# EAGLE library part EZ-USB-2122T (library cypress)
Microcontroller with USB port

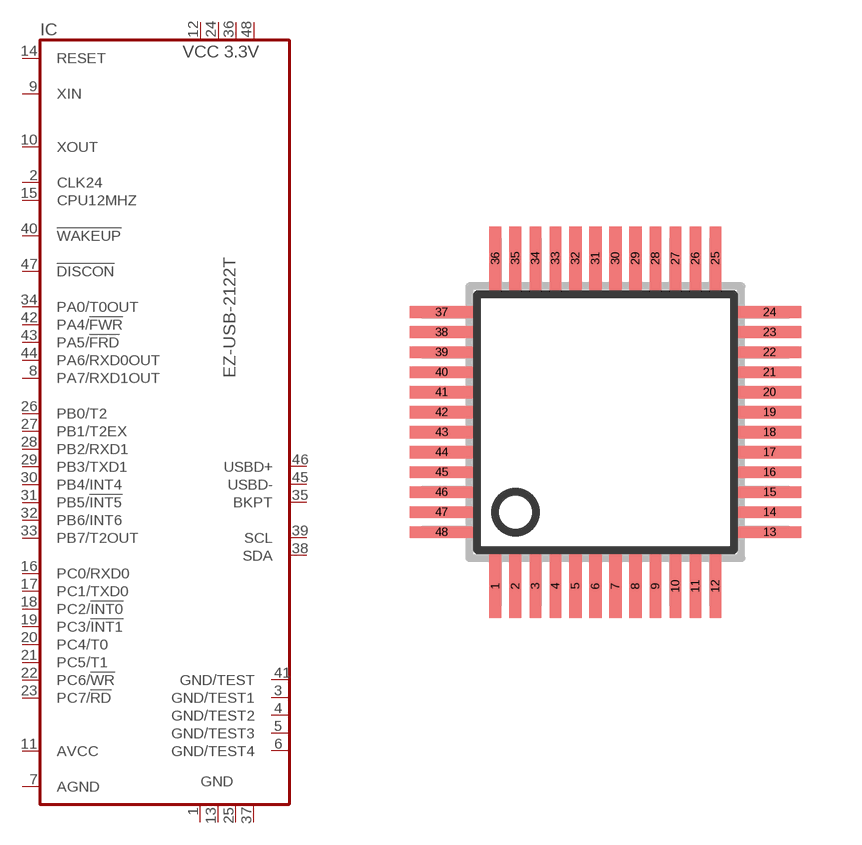
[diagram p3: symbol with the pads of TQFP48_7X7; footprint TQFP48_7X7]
Designator prefix IC

## EZ-USB-2122T (OC_FARNELL: unknown; OC_NEWARK: unknown)  [TQFP48_7X7]
1  GND  pwr
2  CLK24  out
3  GND/TEST1  pwr
4  GND/TEST2  pwr
5  GND/TEST3  pwr
6  GND/TEST4  pwr
7  AGND  pwr
8  PA7/RXD1OUT
9  XIN  in
10  XOUT  out
11  AVCC  pwr
12  VCC3.3  pwr
13  GND  pwr
14  RESET  in
15  CPU12MHZ  in
16  PC0/RXD0
17  PC1/TXD0
18  PC2/!INT0
19  PC3/!INT1
20  PC4/T0
21  PC5/T1
22  PC6/!WR
23  PC7/!RD
24  VCC3.3  pwr
25  GND  pwr
26  PB0/T2
27  PB1/T2EX
28  PB2/RXD1
29  PB3/TXD1
30  PB4/INT4
31  PB5/!INT5
32  PB6/INT6
33  PB7/T2OUT
34  PA0/T0OUT
35  BKPT  out
36  VCC3.3  pwr
37  GND  pwr
38  SDA  oc
39  SCL  oc
40  !WAKEUP  in
41  GND/TEST  pwr
42  PA4/!FWR
43  PA5/!FRD
44  PA6/RXD0OUT
45  USBD-  hiz
46  USBD+  hiz
47  !DISCON  out
48  VCC3.3  pwr

## Footprint TQFP48_7X7 (pad centres in mm)
Thin Quad Flat Package from SMD-IPC.lbr SQFP48 7x7
smd 0.3 x 1.6: 1 -2.75,-4.1; 2 -2.25,-4.1; 3 -1.75,-4.1; 4 -1.25,-4.1; 5 -0.75,-4.1; 6 -0.25,-4.1; 7 0.25,-4.1; 8 0.75,-4.1; 9 1.25,-4.1; 10 1.75,-4.1; 11 2.25,-4.1; 12 2.75,-4.1; 25 2.75,4.1; 26 2.25,4.1; 27 1.75,4.1; 28 1.25,4.1; 29 0.75,4.1; 30 0.25,4.1; 31 -0.25,4.1; 32 -0.75,4.1; 33 -1.25,4.1; 34 -1.75,4.1; 35 -2.25,4.1; 36 -2.75,4.1
smd 1.6 x 0.3: 13 4.1,-2.75; 14 4.1,-2.25; 15 4.1,-1.75; 16 4.1,-1.25; 17 4.1,-0.75; 18 4.1,-0.25; 19 4.1,0.25; 20 4.1,0.75; 21 4.1,1.25; 22 4.1,1.75; 23 4.1,2.25; 24 4.1,2.75; 37 -4.1,2.75; 38 -4.1,2.25; 39 -4.1,1.75; 40 -4.1,1.25; 41 -4.1,0.75; 42 -4.1,0.25; 43 -4.1,-0.25; 44 -4.1,-0.75; 45 -4.1,-1.25; 46 -4.1,-1.75; 47 -4.1,-2.25; 48 -4.1,-2.75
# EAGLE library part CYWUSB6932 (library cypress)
WirelessUSB LS 2.4 GHz DSSS Radio SoC Source: http://v4.cypress.com/cfuploads/img/products/cywusb6934.pdf

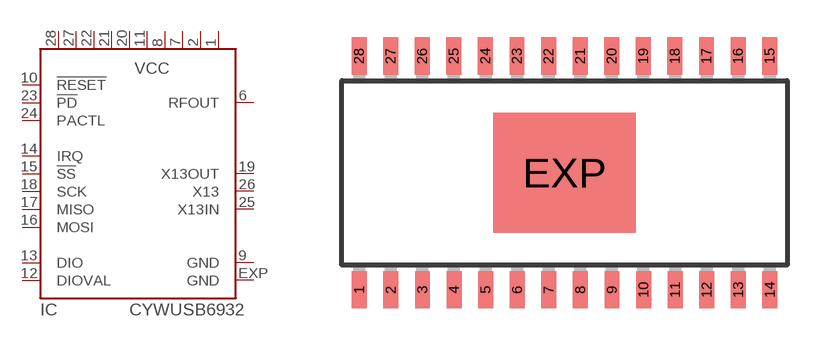
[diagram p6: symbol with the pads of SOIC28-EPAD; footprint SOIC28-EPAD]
Designator prefix IC

## CYWUSB6932-SE28 (OC_FARNELL: unknown; OC_NEWARK: unknown)  [SOIC28-EPAD]
1  VCC  pwr
2  VCC  pwr
6  RFOUT  out
7  VCC  pwr
8  VCC  pwr
9  GND  pwr
10  !RESET  in
11  VCC  pwr
12  DIOVAL
13  DIO
14  IRQ  hiz
15  !SS  in
16  MOSI  in
17  MISO  hiz
18  SCK  in
19  X13OUT  out
20  VCC  pwr
21  VCC  pwr
22  VCC  pwr
23  !PD  in
24  PACTL
25  X13IN  in
26  X13  in
27  VCC  pwr
28  VCC  pwr
EXP  GND  pwr

## Footprint SOIC28-EPAD (pad centres in mm)
28-pin (300-Mil) SOIC EPAD SE28.3 Source: http://v4.cypress.com/cfuploads/img/products/cywusb6934.pdf
smd 0.6 x 1.5: 1 -8.25,-4.7; 2 -6.98,-4.7; 3 -5.71,-4.7; 4 -4.44,-4.7; 5 -3.17,-4.7; 6 -1.9,-4.7; 7 -0.63,-4.7; 8 0.64,-4.7; 9 1.91,-4.7; 10 3.18,-4.7; 11 4.45,-4.7; 12 5.72,-4.7; 13 6.99,-4.7; 14 8.26,-4.7; 15 8.25,4.7; 16 6.98,4.7; 17 5.71,4.7; 18 4.44,4.7; 19 3.17,4.7; 20 1.9,4.7; 21 0.63,4.7; 22 -0.64,4.7; 23 -1.91,4.7; 24 -3.18,4.7; 25 -4.45,4.7; 26 -5.72,4.7; 27 -6.99,4.7; 28 -8.26,4.7
smd 5.715 x 4.826: EXP 0,0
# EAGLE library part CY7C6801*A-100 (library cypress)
EZ-USB FX2LP (TM) USB Microcontroller Source: http://www.cypress.com .. cy7c68013a_5.pdf

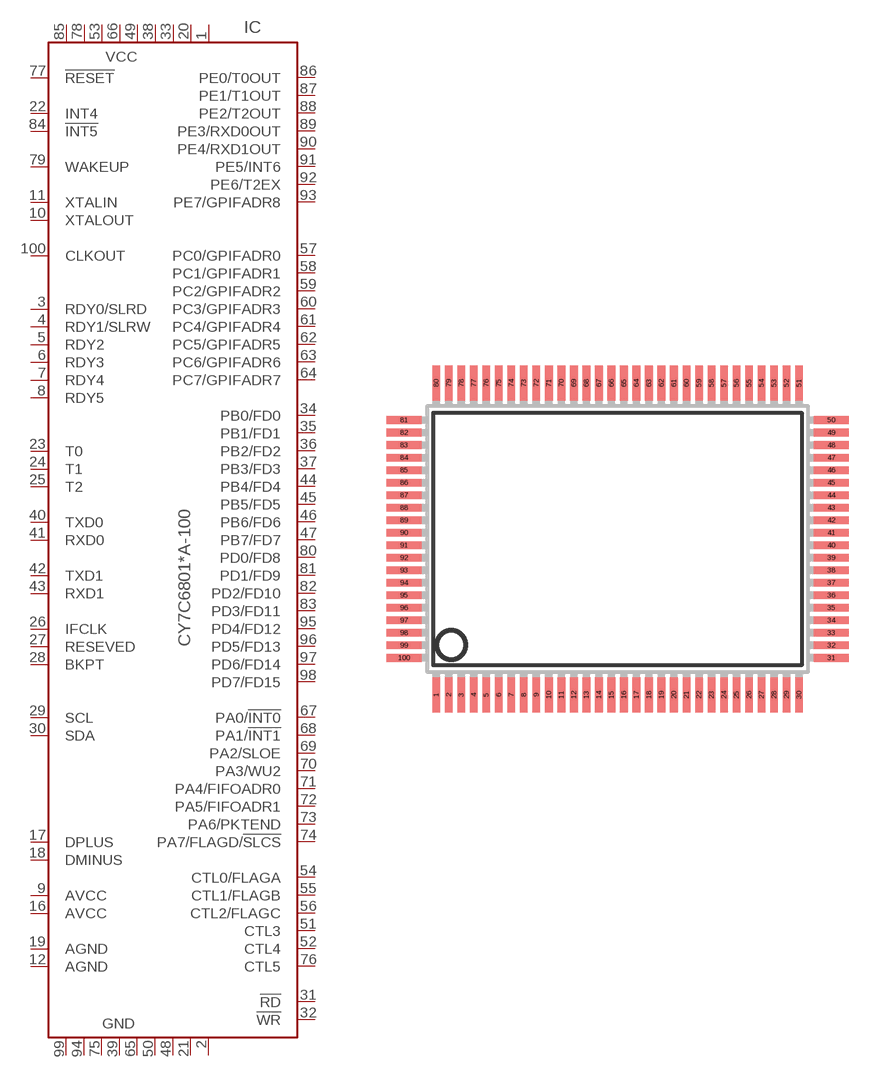
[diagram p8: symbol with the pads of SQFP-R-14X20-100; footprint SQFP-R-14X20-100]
Designator prefix IC

## CY7C68013A-100AXC (MF: CYPRESS SEMICONDUCTOR CORPORAT; MPN: CY7C68013A-100AXC; OC_FARNELL: 1269130; OC_NEWARK: 19M7106), CY7C68014A-100AXC (MF: CYPRESS SEMICONDUCTOR CORPORAT; MPN: CY7C68014A-100AXC; OC_FARNELL: 1269135; OC_NEWARK: 19M7117)  [SQFP-R-14X20-100]
1  VCC  in
2  GND  in
3  RDY0/SLRD  in
4  RDY1/SLRW  in
5  RDY2  in
6  RDY3  in
7  RDY4  in
8  RDY5  in
9  AVCC  in
10  XTALOUT  in
11  XTALIN  in
12  AGND  in
16  AVCC  in
17  DPLUS
18  DMINUS
19  AGND  in
20  VCC  in
21  GND  in
22  INT4  out
23  T0  out
24  T1  out
25  T2  out
26  IFCLK
27  RESEVED  in
28  BKPT  out
29  SCL  out
30  SDA
31  !RD  out
32  !WR  out
33  VCC  in
34  PB0/FD0
35  PB1/FD1
36  PB2/FD2
37  PB3/FD3
38  VCC  in
39  GND  in
40  TXD0  in
41  RXD0  out
42  TXD1  in
43  RXD1  out
44  PB4/FD4
45  PB5/FD5
46  PB6/FD6
47  PB7/FD7
48  GND  in
49  VCC  in
50  GND  in
51  CTL3  in
52  CTL4  in
53  VCC  in
54  CTL0/FLAGA  out
55  CTL1/FLAGB  out
56  CTL2/FLAGC  out
57  PC0/GPIFADR0
58  PC1/GPIFADR1
59  PC2/GPIFADR2
60  PC3/GPIFADR3
61  PC4/GPIFADR4
62  PC5/GPIFADR5
63  PC6/GPIFADR6
64  PC7/GPIFADR7
65  GND  in
66  VCC  in
67  PA0/!INT0
68  PA1/!INT1
69  PA2/SLOE
70  PA3/WU2
71  PA4/FIFOADR0
72  PA5/FIFOADR1
73  PA6/PKTEND
74  PA7/FLAGD/!SLCS
75  GND  in
76  CTL5
77  !RESET
78  VCC  in
79  WAKEUP  in
80  PD0/FD8
81  PD1/FD9
82  PD2/FD10
83  PD3/FD11
84  !INT5  out
85  VCC  in
86  PE0/T0OUT
87  PE1/T1OUT
88  PE2/T2OUT
89  PE3/RXD0OUT
90  PE4/RXD1OUT
91  PE5/INT6
92  PE6/T2EX
93  PE7/GPIFADR8
94  GND  in
95  PD4/FD12
96  PD5/FD13
97  PD6/FD14
98  PD7/FD15
99  GND  in
100  CLKOUT  in

## CY7C68013A-100AXI (MPN: CY7C68013A-100AXI; OC_FARNELL: unknown; OC_NEWARK: 19M7107)  [SQFP-R-14X20-100]
Pads as for SQFP-R-14X20-100

## Footprint SQFP-R-14X20-100 (pad centres in mm)
QFP100 shrink quad flat pack, rectangle
smd 0.4 x 1.8: 1 -9.425,-8.1; 2 -8.775,-8.1; 3 -8.125,-8.1; 4 -7.475,-8.1; 5 -6.825,-8.1; 6 -6.175,-8.1; 7 -5.525,-8.1; 8 -4.875,-8.1; 9 -4.225,-8.1; 10 -3.575,-8.1; 11 -2.925,-8.1; 12 -2.275,-8.1; 13 -1.625,-8.1; 14 -0.975,-8.1; 15 -0.325,-8.1; 16 0.325,-8.1; 17 0.975,-8.1; 18 1.625,-8.1; 19 2.275,-8.1; 20 2.925,-8.1; 21 3.575,-8.1; 22 4.225,-8.1; 23 4.875,-8.1; 24 5.525,-8.1; 25 6.175,-8.1; 26 6.825,-8.1; 27 7.475,-8.1; 28 8.125,-8.1; 29 8.775,-8.1; 30 9.425,-8.1; 51 9.425,8.1; 52 8.775,8.1; 53 8.125,8.1; 54 7.475,8.1; 55 6.825,8.1; 56 6.175,8.1; 57 5.525,8.1; 58 4.875,8.1; 59 4.225,8.1; 60 3.575,8.1; 61 2.925,8.1; 62 2.275,8.1; 63 1.625,8.1; 64 0.975,8.1; 65 0.325,8.1; 66 -0.325,8.1; 67 -0.975,8.1; 68 -1.625,8.1; 69 -2.275,8.1; 70 -2.925,8.1; 71 -3.575,8.1; 72 -4.225,8.1; 73 -4.875,8.1; 74 -5.525,8.1; 75 -6.175,8.1; 76 -6.825,8.1; 77 -7.475,8.1; 78 -8.125,8.1; 79 -8.775,8.1; 80 -9.425,8.1
smd 1.8 x 0.4: 31 11.1,-6.175; 32 11.1,-5.525; 33 11.1,-4.875; 34 11.1,-4.225; 35 11.1,-3.575; 36 11.1,-2.925; 37 11.1,-2.275; 38 11.1,-1.625; 39 11.1,-0.975; 40 11.1,-0.325; 41 11.1,0.325; 42 11.1,0.975; 43 11.1,1.625; 44 11.1,2.275; 45 11.1,2.925; 46 11.1,3.575; 47 11.1,4.225; 48 11.1,4.875; 49 11.1,5.525; 50 11.1,6.175; 81 -11.1,6.175; 82 -11.1,5.525; 83 -11.1,4.875; 84 -11.1,4.225; 85 -11.1,3.575; 86 -11.1,2.925; 87 -11.1,2.275; 88 -11.1,1.625; 89 -11.1,0.975; 90 -11.1,0.325; 91 -11.1,-0.325; 92 -11.1,-0.975; 93 -11.1,-1.625; 94 -11.1,-2.275; 95 -11.1,-2.925; 96 -11.1,-3.575; 97 -11.1,-4.225; 98 -11.1,-4.875; 99 -11.1,-5.525; 100 -11.1,-6.175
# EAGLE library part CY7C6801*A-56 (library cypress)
EZ-USB FX2LP (TM) USB Microcontroller Source: http://www.cypress.com .. cy7c68013a_5.pdf

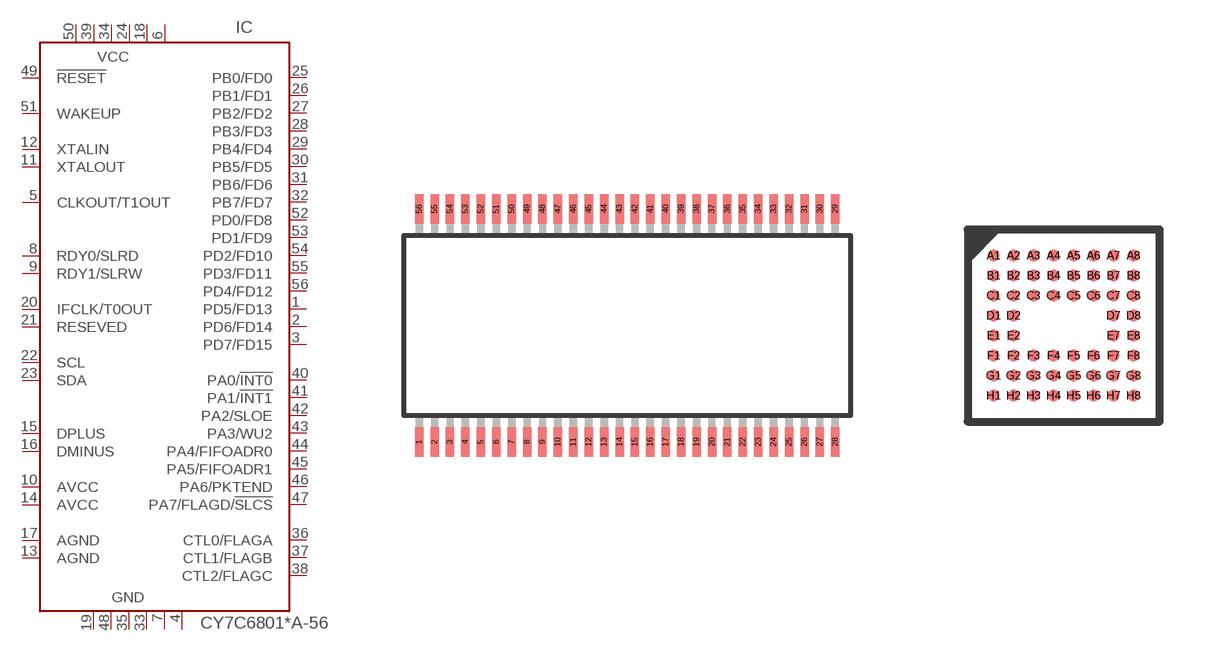
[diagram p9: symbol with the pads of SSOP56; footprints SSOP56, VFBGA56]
Designator prefix IC

## CY7C68013A-56PVXC (MF: CYPRESS SEMICONDUCTOR CORPORAT; MPN: CY7C68013A-56PVXC; OC_FARNELL: 1269134; OC_NEWARK: 19M7114), CY7C68014A-56PVXC (MF: CYPRESS SEMICONDUCTOR CORPORAT; MPN: CY7C68014A-56PVXC; OC_FARNELL: 1269140; OC_NEWARK: 19M7121)  [SSOP56]
1  PD5/FD13
2  PD6/FD14
3  PD7/FD15
4  GND  in
5  CLKOUT/T1OUT  in
6  VCC  in
7  GND  in
8  RDY0/SLRD  in
9  RDY1/SLRW  in
10  AVCC  in
11  XTALOUT  in
12  XTALIN  in
13  AGND  in
14  AVCC  in
15  DPLUS
16  DMINUS
17  AGND  in
18  VCC  in
19  GND  in
20  IFCLK/T0OUT
21  RESEVED  in
22  SCL  out
23  SDA
24  VCC  in
25  PB0/FD0
26  PB1/FD1
27  PB2/FD2
28  PB3/FD3
29  PB4/FD4
30  PB5/FD5
31  PB6/FD6
32  PB7/FD7
33  GND  in
34  VCC  in
35  GND  in
36  CTL0/FLAGA  out
37  CTL1/FLAGB  out
38  CTL2/FLAGC  out
39  VCC  in
40  PA0/!INT0
41  PA1/!INT1
42  PA2/SLOE
43  PA3/WU2
44  PA4/FIFOADR0
45  PA5/FIFOADR1
46  PA6/PKTEND
47  PA7/FLAGD/!SLCS
48  GND  in
49  !RESET  in
50  VCC  in
51  WAKEUP  in
52  PD0/FD8
53  PD1/FD9
54  PD2/FD10
55  PD3/FD11
56  PD4/FD12

## CY7C68013A-56BAXC (MF: CYPRESS SEMICONDUCTOR CORPORAT; MPN: CY7C68013A-56BAXC; OC_FARNELL: 1269132; OC_NEWARK: 19M7110), CY7C68014A-56BAXC (MPN: CY7C68014A-56BAXC; OC_FARNELL: 1269138; OC_NEWARK: 23M5564)  [VFBGA56]
A1  RDY0/SLRD  in
A2  PD7/FD15
A3  PD5/FD13
A4  GND  in
A5  VCC  in
A6  PD3/FD11
A7  PD1/FD9
A8  PD0/FD8
B1  RDY1/SLRW  in
B2  CLKOUT/T1OUT  in
B3  PD4/FD12
B4  GND  in
B5  VCC  in
B6  PD2/FD10
B7  WAKEUP  in
B8  !RESET  in
C1  XTALIN  in
C2  XTALOUT  in
C3  PD6/FD14
C4  GND  in
C5  VCC  in
C6  PA7/FLAGD/!SLCS
C7  PA6/PKTEND
C8  PA5/FIFOADR1
D1  AVCC  in
D2  AVCC  in
D7  GND  in
D8  GND  in
E1  DMINUS
E2  DPLUS
E7  VCC  in
E8  VCC  in
F1  AGND  in
F2  AGND  in
F3  SCL  out
F4  PB1/FD1
F5  PB6/FD6
F6  PA4/FIFOADR0
F7  PA3/WU2
F8  PA2/SLOE
G1  VCC  in
G2  IFCLK/T0OUT
G3  SDA
G4  PB3/FD3
G5  PB5/FD5
G6  PA1/!INT1
G7  CTL1/FLAGB  out
G8  PA0/!INT0
H1  GND  in
H2  RESEVED  in
H3  PB0/FD0
H4  PB2/FD2
H5  PB4/FD4
H6  PB7/FD7
H7  CTL0/FLAGA  out
H8  CTL2/FLAGC  out

## CY7C68013A-56PVXI (MPN: CY7C68013A-56PVXI; OC_FARNELL: 1761053; OC_NEWARK: 19M7116)  [SSOP56]
Pads as for SSOP56

## Footprint SSOP56 (pad centres in mm)
56-lead Shrunk Small Outline Package O56 Source: Source: http://www.cypress.com .. cy7c68013a_5.pdf
smd 0.35 x 1.2: 1 -8.572,-4.8; 2 -7.938,-4.8; 3 -7.303,-4.8; 4 -6.668,-4.8; 5 -6.032,-4.8; 6 -5.397,-4.8; 7 -4.763,-4.8; 8 -4.128,-4.8; 9 -3.493,-4.8; 10 -2.857,-4.8; 11 -2.223,-4.8; 12 -1.587,-4.8; 13 -0.953,-4.8; 14 -0.318,-4.8; 15 0.318,-4.8; 16 0.953,-4.8; 17 1.587,-4.8; 18 2.223,-4.8; 19 2.857,-4.8; 20 3.493,-4.8; 21 4.128,-4.8; 22 4.763,-4.8; 23 5.397,-4.8; 24 6.032,-4.8; 25 6.668,-4.8; 26 7.303,-4.8; 27 7.938,-4.8; 28 8.572,-4.8; 29 8.572,4.8; 30 7.938,4.8; 31 7.303,4.8; 32 6.668,4.8; 33 6.032,4.8; 34 5.397,4.8; 35 4.763,4.8; 36 4.128,4.8; 37 3.493,4.8; 38 2.857,4.8; 39 2.223,4.8; 40 1.587,4.8; 41 0.953,4.8; 42 0.318,4.8; 43 -0.318,4.8; 44 -0.953,4.8; 45 -1.587,4.8; 46 -2.223,4.8; 47 -2.857,4.8; 48 -3.493,4.8; 49 -4.128,4.8; 50 -4.763,4.8; 51 -5.397,4.8; 52 -6.032,4.8; 53 -6.668,4.8; 54 -7.303,4.8; 55 -7.938,4.8; 56 -8.572,4.8

## Footprint VFBGA56 (pad centres in mm)
VFBGA 56 Source: Source: http://www.cypress.com .. cy7c68013a_5.pdf
smd 0.3 x 0.3: A1 -1.75,1.75; A2 -1.25,1.75; A3 -0.75,1.75; A4 -0.25,1.75; A5 0.25,1.75; A6 0.75,1.75; A7 1.25,1.75; A8 1.75,1.75; B1 -1.75,1.25; B2 -1.25,1.25; B3 -0.75,1.25; B4 -0.25,1.25; B5 0.25,1.25; B6 0.75,1.25; B7 1.25,1.25; B8 1.75,1.25; C1 -1.75,0.75; C2 -1.25,0.75; C3 -0.75,0.75; C4 -0.25,0.75; C5 0.25,0.75; C6 0.75,0.75; C7 1.25,0.75; C8 1.75,0.75; D1 -1.75,0.25; D2 -1.25,0.25; D7 1.25,0.25; D8 1.75,0.25; E1 -1.75,-0.25; E2 -1.25,-0.25; E7 1.25,-0.25; E8 1.75,-0.25; F1 -1.75,-0.75; F2 -1.25,-0.75; F3 -0.75,-0.75; F4 -0.25,-0.75; F5 0.25,-0.75; F6 0.75,-0.75; F7 1.25,-0.75; F8 1.75,-0.75; G1 -1.75,-1.25; G2 -1.25,-1.25; G3 -0.75,-1.25; G4 -0.25,-1.25; G5 0.25,-1.25; G6 0.75,-1.25; G7 1.25,-1.25; G8 1.75,-1.25; H1 -1.75,-1.75; H2 -1.25,-1.75; H3 -0.75,-1.75; H4 -0.25,-1.75; H5 0.25,-1.75; H6 0.75,-1.75; H7 1.25,-1.75; H8 1.75,-1.75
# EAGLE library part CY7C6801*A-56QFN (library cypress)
EZ-USB FX2LP (TM) USB Microcontroller Source: http://www.cypress.com .. cy7c68013a_5.pdf

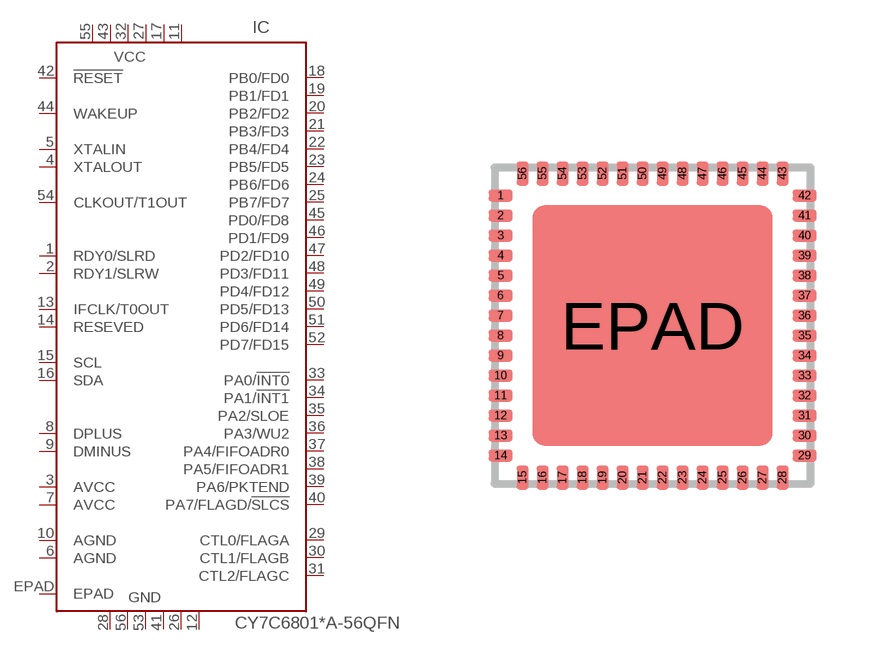
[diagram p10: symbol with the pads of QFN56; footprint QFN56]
Designator prefix IC

## CY7C68013A-56QFNLFXC (OC_FARNELL: unknown; OC_NEWARK: unknown), CY7C68014A-56QFNLFXC (OC_FARNELL: unknown; OC_NEWARK: unknown), CY7C68015A-56QFNLFXC (OC_FARNELL: unknown; OC_NEWARK: unknown), CY7C68016A-56QFNLFXC (OC_FARNELL: unknown; OC_NEWARK: unknown)  [QFN56]
1  RDY0/SLRD  in
2  RDY1/SLRW  in
3  AVCC  in
4  XTALOUT  in
5  XTALIN  in
6  AGND  in
7  AVCC  in
8  DPLUS
9  DMINUS
10  AGND  in
11  VCC  in
12  GND  in
13  IFCLK/T0OUT
14  RESEVED  in
15  SCL  out
16  SDA
17  VCC  in
18  PB0/FD0
19  PB1/FD1
20  PB2/FD2
21  PB3/FD3
22  PB4/FD4
23  PB5/FD5
24  PB6/FD6
25  PB7/FD7
26  GND  in
27  VCC  in
28  GND  in
29  CTL0/FLAGA  out
30  CTL1/FLAGB  out
31  CTL2/FLAGC  out
32  VCC  in
33  PA0/!INT0
34  PA1/!INT1
35  PA2/SLOE
36  PA3/WU2
37  PA4/FIFOADR0
38  PA5/FIFOADR1
39  PA6/PKTEND
40  PA7/FLAGD/!SLCS
41  GND  in
42  !RESET  in
43  VCC  in
44  WAKEUP  in
45  PD0/FD8
46  PD1/FD9
47  PD2/FD10
48  PD3/FD11
49  PD4/FD12
50  PD5/FD13
51  PD6/FD14
52  PD7/FD15
53  GND  in
54  CLKOUT/T1OUT  in
55  VCC  in
56  GND  in
EPAD  EPAD  pas

## CY7C68013A-56QFNLFXI (OC_FARNELL: unknown; OC_NEWARK: unknown)  [QFN56]
Pads as for QFN56

## Footprint QFN56 (pad centres in mm)
56-Lead QFN 8 x 8 mm LF56A Source: Source: http://www.cypress.com .. cy7c68013a_5.pdf
smd 0.6 x 0.3: 1 -3.8,3.25; 2 -3.8,2.75; 3 -3.8,2.25; 4 -3.8,1.75; 5 -3.8,1.25; 6 -3.8,0.75; 7 -3.8,0.25; 8 -3.8,-0.25; 9 -3.8,-0.75; 10 -3.8,-1.25; 11 -3.8,-1.75; 12 -3.8,-2.25; 13 -3.8,-2.75; 14 -3.8,-3.25; 29 3.8,-3.25; 30 3.8,-2.75; 31 3.8,-2.25; 32 3.8,-1.75; 33 3.8,-1.25; 34 3.8,-0.75; 35 3.8,-0.25; 36 3.8,0.25; 37 3.8,0.75; 38 3.8,1.25; 39 3.8,1.75; 40 3.8,2.25; 41 3.8,2.75; 42 3.8,3.25
smd 0.3 x 0.6: 15 -3.25,-3.8; 16 -2.75,-3.8; 17 -2.25,-3.8; 18 -1.75,-3.8; 19 -1.25,-3.8; 20 -0.75,-3.8; 21 -0.25,-3.8; 22 0.25,-3.8; 23 0.75,-3.8; 24 1.25,-3.8; 25 1.75,-3.8; 26 2.25,-3.8; 27 2.75,-3.8; 28 3.25,-3.8; 43 3.25,3.8; 44 2.75,3.8; 45 2.25,3.8; 46 1.75,3.8; 47 1.25,3.8; 48 0.75,3.8; 49 0.25,3.8; 50 -0.25,3.8; 51 -0.75,3.8; 52 -1.25,3.8; 53 -1.75,3.8; 54 -2.25,3.8; 55 -2.75,3.8; 56 -3.25,3.8
smd 6 x 6: EPAD 0,0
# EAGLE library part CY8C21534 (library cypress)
PSoC® Programmable System-on-Chip? M8C Processor Speeds to 24 MHz Source: http://www.cypress.com .. 38-12025_0P_V.pdf

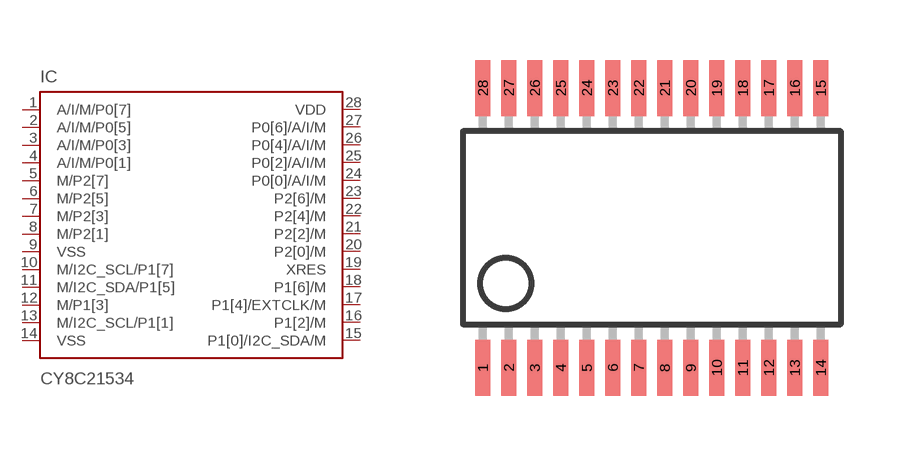
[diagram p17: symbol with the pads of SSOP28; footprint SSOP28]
Designator prefix IC

## CY8C21534 (MPN: CY8C21534-12PVXE; OC_FARNELL: 1321733; OC_NEWARK: 19M7172)  [SSOP28]
1  A/I/M/P0[7]
2  A/I/M/P0[5]
3  A/I/M/P0[3]
4  A/I/M/P0[1]
5  M/P2[7]
6  M/P2[5]
7  M/P2[3]
8  M/P2[1]
9  VSS  pwr
10  M/I2C_SCL/P1[7]
11  M/I2C_SDA/P1[5]
12  M/P1[3]
13  M/I2C_SCL/P1[1]
14  VSS  pwr
15  P1[0]/I2C_SDA/M
16  P1[2]/M
17  P1[4]/EXTCLK/M
18  P1[6]/M
19  XRES  in
20  P2[0]/M
21  P2[2]/M
22  P2[4]/M
23  P2[6]/M
24  P0[0]/A/I/M
25  P0[2]/A/I/M
26  P0[4]/A/I/M
27  P0[6]/A/I/M
28  VDD  pwr

## Footprint SSOP28 (pad centres in mm)
Small Shrink Outline Package 28-Pin (210-MIL) SSOP Source: http://www.cypress.com .. 38-12025_0P_V.pdf
smd 0.38 x 1.4: 1 -4.225,-3.5; 2 -3.575,-3.5; 3 -2.925,-3.5; 4 -2.275,-3.5; 5 -1.625,-3.5; 6 -0.975,-3.5; 7 -0.325,-3.5; 8 0.325,-3.5; 9 0.975,-3.5; 10 1.625,-3.5; 11 2.275,-3.5; 12 2.925,-3.5; 13 3.575,-3.5; 14 4.225,-3.5; 15 4.225,3.5; 16 3.575,3.5; 17 2.925,3.5; 18 2.275,3.5; 19 1.625,3.5; 20 0.975,3.5; 21 0.325,3.5; 22 -0.325,3.5; 23 -0.975,3.5; 24 -1.625,3.5; 25 -2.275,3.5; 26 -2.925,3.5; 27 -3.575,3.5; 28 -4.225,3.5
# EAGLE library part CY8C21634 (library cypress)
PSoC® Programmable System-on-Chip? M8C Processor Speeds to 24 MHz Source: http://www.cypress.com .. 38-12025_0P_V.pdf

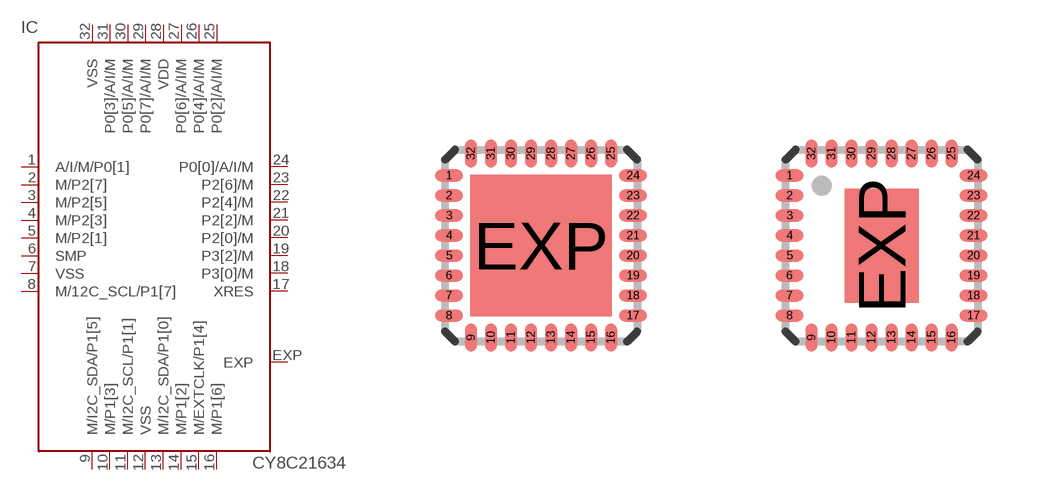
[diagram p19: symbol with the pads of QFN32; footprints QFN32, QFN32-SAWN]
Designator prefix IC

## CY8C21634 (OC_FARNELL: 1321734; OC_NEWARK: unknown)  [QFN32]
1  A/I/M/P0[1]
2  M/P2[7]
3  M/P2[5]
4  M/P2[3]
5  M/P2[1]
6  SMP  pwr
7  VSS  pwr
8  M/12C_SCL/P1[7]
9  M/I2C_SDA/P1[5]
10  M/P1[3]
11  M/I2C_SCL/P1[1]
12  VSS  pwr
13  M/I2C_SDA/P1[0]
14  M/P1[2]
15  M/EXTCLK/P1[4]
16  M/P1[6]
17  XRES  in
18  P3[0]/M
19  P3[2]/M
20  P2[0]/M
21  P2[2]/M
22  P2[4]/M
23  P2[6]/M
24  P0[0]/A/I/M
25  P0[2]/A/I/M
26  P0[4]/A/I/M
27  P0[6]/A/I/M
28  VDD  pwr
29  P0[7]/A/I/M
30  P0[5]/A/I/M
31  P0[3]/A/I/M
32  VSS  pwr
EXP  EXP  pas

## CY8C21634SAWN (OC_FARNELL: unknown; OC_NEWARK: unknown)  [QFN32-SAWN]
Pads as for QFN32

## Footprint QFN32 (pad centres in mm)
32-Pin (5x5 mm) QFN Source: http://www.cypress.com .. 38-12025_0P_V.pdf
smd 0.7 x 0.3: 1 -2.3,1.75; 2 -2.3,1.25; 3 -2.3,0.75; 4 -2.3,0.25; 5 -2.3,-0.25; 6 -2.3,-0.75; 7 -2.3,-1.25; 8 -2.3,-1.75; 17 2.3,-1.75; 18 2.3,-1.25; 19 2.3,-0.75; 20 2.3,-0.25; 21 2.3,0.25; 22 2.3,0.75; 23 2.3,1.25; 24 2.3,1.75
smd 0.3 x 0.7: 9 -1.75,-2.3; 10 -1.25,-2.3; 11 -0.75,-2.3; 12 -0.25,-2.3; 13 0.25,-2.3; 14 0.75,-2.3; 15 1.25,-2.3; 16 1.75,-2.3; 25 1.75,2.3; 26 1.25,2.3; 27 0.75,2.3; 28 0.25,2.3; 29 -0.25,2.3; 30 -0.75,2.3; 31 -1.25,2.3; 32 -1.75,2.3
smd 3.53 x 3.53: EXP 0,0

## Footprint QFN32-SAWN (pad centres in mm)
32-Pin (5x5 mm Sawn) QFN Source: http://www.cypress.com .. 38-12025_0P_V.pdf
smd 0.7 x 0.3: 1 -2.3,1.75; 2 -2.3,1.25; 3 -2.3,0.75; 4 -2.3,0.25; 5 -2.3,-0.25; 6 -2.3,-0.75; 7 -2.3,-1.25; 8 -2.3,-1.75; 17 2.3,-1.75; 18 2.3,-1.25; 19 2.3,-0.75; 20 2.3,-0.25; 21 2.3,0.25; 22 2.3,0.75; 23 2.3,1.25; 24 2.3,1.75
smd 0.3 x 0.7: 9 -1.75,-2.3; 10 -1.25,-2.3; 11 -0.75,-2.3; 12 -0.25,-2.3; 13 0.25,-2.3; 14 0.75,-2.3; 15 1.25,-2.3; 16 1.75,-2.3; 25 1.75,2.3; 26 1.25,2.3; 27 0.75,2.3; 28 0.25,2.3; 29 -0.25,2.3; 30 -0.75,2.3; 31 -1.25,2.3; 32 -1.75,2.3
smd 1.85 x 2.85: EXP 0,0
